VERSION 5.7 ;
  NOWIREEXTENSIONATPIN ON ;
  DIVIDERCHAR "/" ;
  BUSBITCHARS "[]" ;
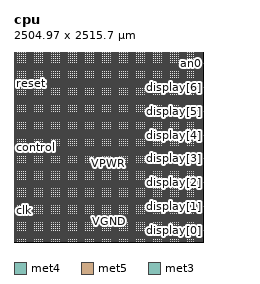
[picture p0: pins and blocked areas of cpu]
MACRO cpu
  CLASS BLOCK ;
  FOREIGN cpu ;
  ORIGIN 0.000 0.000 ;
  SIZE 2504.975 BY 2515.695 ;
  PIN VGND
    DIRECTION INOUT ;
    USE GROUND ;
    PORT
      LAYER met4 ;
        RECT 13.020 10.640 14.620 2502.640 ;
    END
    PORT
      LAYER met4 ;
        RECT 38.020 10.640 39.620 2502.640 ;
    END
    PORT
      LAYER met4 ;
        RECT 63.020 10.640 64.620 2502.640 ;
    END
    PORT
      LAYER met4 ;
        RECT 88.020 10.640 89.620 2502.640 ;
    END
    PORT
      LAYER met4 ;
        RECT 113.020 10.640 114.620 2502.640 ;
    END
    PORT
      LAYER met4 ;
        RECT 138.020 10.640 139.620 2502.640 ;
    END
    PORT
      LAYER met4 ;
        RECT 163.020 10.640 164.620 2502.640 ;
    END
    PORT
      LAYER met4 ;
        RECT 188.020 10.640 189.620 2502.640 ;
    END
    PORT
      LAYER met4 ;
        RECT 213.020 10.640 214.620 2502.640 ;
    END
    PORT
      LAYER met4 ;
        RECT 238.020 10.640 239.620 2502.640 ;
    END
    PORT
      LAYER met4 ;
        RECT 263.020 10.640 264.620 2502.640 ;
    END
    PORT
      LAYER met4 ;
        RECT 288.020 10.640 289.620 2502.640 ;
    END
    PORT
      LAYER met4 ;
        RECT 313.020 10.640 314.620 2502.640 ;
    END
    PORT
      LAYER met4 ;
        RECT 338.020 10.640 339.620 2502.640 ;
    END
    PORT
      LAYER met4 ;
        RECT 363.020 10.640 364.620 2502.640 ;
    END
    PORT
      LAYER met4 ;
        RECT 388.020 10.640 389.620 2502.640 ;
    END
    PORT
      LAYER met4 ;
        RECT 413.020 10.640 414.620 2502.640 ;
    END
    PORT
      LAYER met4 ;
        RECT 438.020 10.640 439.620 2502.640 ;
    END
    PORT
      LAYER met4 ;
        RECT 463.020 10.640 464.620 2502.640 ;
    END
    PORT
      LAYER met4 ;
        RECT 488.020 10.640 489.620 2502.640 ;
    END
    PORT
      LAYER met4 ;
        RECT 513.020 10.640 514.620 2502.640 ;
    END
    PORT
      LAYER met4 ;
        RECT 538.020 10.640 539.620 2502.640 ;
    END
    PORT
      LAYER met4 ;
        RECT 563.020 10.640 564.620 2502.640 ;
    END
    PORT
      LAYER met4 ;
        RECT 588.020 10.640 589.620 2502.640 ;
    END
    PORT
      LAYER met4 ;
        RECT 613.020 10.640 614.620 2502.640 ;
    END
    PORT
      LAYER met4 ;
        RECT 638.020 10.640 639.620 2502.640 ;
    END
    PORT
      LAYER met4 ;
        RECT 663.020 10.640 664.620 2502.640 ;
    END
    PORT
      LAYER met4 ;
        RECT 688.020 10.640 689.620 2502.640 ;
    END
    PORT
      LAYER met4 ;
        RECT 713.020 10.640 714.620 2502.640 ;
    END
    PORT
      LAYER met4 ;
        RECT 738.020 10.640 739.620 2502.640 ;
    END
    PORT
      LAYER met4 ;
        RECT 763.020 10.640 764.620 2502.640 ;
    END
    PORT
      LAYER met4 ;
        RECT 788.020 10.640 789.620 2502.640 ;
    END
    PORT
      LAYER met4 ;
        RECT 813.020 10.640 814.620 2502.640 ;
    END
    PORT
      LAYER met4 ;
        RECT 838.020 10.640 839.620 2502.640 ;
    END
    PORT
      LAYER met4 ;
        RECT 863.020 10.640 864.620 2502.640 ;
    END
    PORT
      LAYER met4 ;
        RECT 888.020 10.640 889.620 2502.640 ;
    END
    PORT
      LAYER met4 ;
        RECT 913.020 10.640 914.620 2502.640 ;
    END
    PORT
      LAYER met4 ;
        RECT 938.020 10.640 939.620 2502.640 ;
    END
    PORT
      LAYER met4 ;
        RECT 963.020 10.640 964.620 2502.640 ;
    END
    PORT
      LAYER met4 ;
        RECT 988.020 10.640 989.620 2502.640 ;
    END
    PORT
      LAYER met4 ;
        RECT 1013.020 10.640 1014.620 2502.640 ;
    END
    PORT
      LAYER met4 ;
        RECT 1038.020 10.640 1039.620 2502.640 ;
    END
    PORT
      LAYER met4 ;
        RECT 1063.020 10.640 1064.620 2502.640 ;
    END
    PORT
      LAYER met4 ;
        RECT 1088.020 10.640 1089.620 2502.640 ;
    END
    PORT
      LAYER met4 ;
        RECT 1113.020 10.640 1114.620 2502.640 ;
    END
    PORT
      LAYER met4 ;
        RECT 1138.020 10.640 1139.620 2502.640 ;
    END
    PORT
      LAYER met4 ;
        RECT 1163.020 10.640 1164.620 2502.640 ;
    END
    PORT
      LAYER met4 ;
        RECT 1188.020 10.640 1189.620 2502.640 ;
    END
    PORT
      LAYER met4 ;
        RECT 1213.020 10.640 1214.620 2502.640 ;
    END
    PORT
      LAYER met4 ;
        RECT 1238.020 10.640 1239.620 2502.640 ;
    END
    PORT
      LAYER met4 ;
        RECT 1263.020 10.640 1264.620 2502.640 ;
    END
    PORT
      LAYER met4 ;
        RECT 1288.020 10.640 1289.620 2502.640 ;
    END
    PORT
      LAYER met4 ;
        RECT 1313.020 10.640 1314.620 2502.640 ;
    END
    PORT
      LAYER met4 ;
        RECT 1338.020 10.640 1339.620 2502.640 ;
    END
    PORT
      LAYER met4 ;
        RECT 1363.020 10.640 1364.620 2502.640 ;
    END
    PORT
      LAYER met4 ;
        RECT 1388.020 10.640 1389.620 2502.640 ;
    END
    PORT
      LAYER met4 ;
        RECT 1413.020 10.640 1414.620 2502.640 ;
    END
    PORT
      LAYER met4 ;
        RECT 1438.020 10.640 1439.620 2502.640 ;
    END
    PORT
      LAYER met4 ;
        RECT 1463.020 10.640 1464.620 2502.640 ;
    END
    PORT
      LAYER met4 ;
        RECT 1488.020 10.640 1489.620 2502.640 ;
    END
    PORT
      LAYER met4 ;
        RECT 1513.020 10.640 1514.620 2502.640 ;
    END
    PORT
      LAYER met4 ;
        RECT 1538.020 10.640 1539.620 2502.640 ;
    END
    PORT
      LAYER met4 ;
        RECT 1563.020 10.640 1564.620 2502.640 ;
    END
    PORT
      LAYER met4 ;
        RECT 1588.020 10.640 1589.620 2502.640 ;
    END
    PORT
      LAYER met4 ;
        RECT 1613.020 10.640 1614.620 2502.640 ;
    END
    PORT
      LAYER met4 ;
        RECT 1638.020 10.640 1639.620 2502.640 ;
    END
    PORT
      LAYER met4 ;
        RECT 1663.020 10.640 1664.620 2502.640 ;
    END
    PORT
      LAYER met4 ;
        RECT 1688.020 10.640 1689.620 2502.640 ;
    END
    PORT
      LAYER met4 ;
        RECT 1713.020 10.640 1714.620 2502.640 ;
    END
    PORT
      LAYER met4 ;
        RECT 1738.020 10.640 1739.620 2502.640 ;
    END
    PORT
      LAYER met4 ;
        RECT 1763.020 10.640 1764.620 2502.640 ;
    END
    PORT
      LAYER met4 ;
        RECT 1788.020 10.640 1789.620 2502.640 ;
    END
    PORT
      LAYER met4 ;
        RECT 1813.020 10.640 1814.620 2502.640 ;
    END
    PORT
      LAYER met4 ;
        RECT 1838.020 10.640 1839.620 2502.640 ;
    END
    PORT
      LAYER met4 ;
        RECT 1863.020 10.640 1864.620 2502.640 ;
    END
    PORT
      LAYER met4 ;
        RECT 1888.020 10.640 1889.620 2502.640 ;
    END
    PORT
      LAYER met4 ;
        RECT 1913.020 10.640 1914.620 2502.640 ;
    END
    PORT
      LAYER met4 ;
        RECT 1938.020 10.640 1939.620 2502.640 ;
    END
    PORT
      LAYER met4 ;
        RECT 1963.020 10.640 1964.620 2502.640 ;
    END
    PORT
      LAYER met4 ;
        RECT 1988.020 10.640 1989.620 2502.640 ;
    END
    PORT
      LAYER met4 ;
        RECT 2013.020 10.640 2014.620 2502.640 ;
    END
    PORT
      LAYER met4 ;
        RECT 2038.020 10.640 2039.620 2502.640 ;
    END
    PORT
      LAYER met4 ;
        RECT 2063.020 10.640 2064.620 2502.640 ;
    END
    PORT
      LAYER met4 ;
        RECT 2088.020 10.640 2089.620 2502.640 ;
    END
    PORT
      LAYER met4 ;
        RECT 2113.020 10.640 2114.620 2502.640 ;
    END
    PORT
      LAYER met4 ;
        RECT 2138.020 10.640 2139.620 2502.640 ;
    END
    PORT
      LAYER met4 ;
        RECT 2163.020 10.640 2164.620 2502.640 ;
    END
    PORT
      LAYER met4 ;
        RECT 2188.020 10.640 2189.620 2502.640 ;
    END
    PORT
      LAYER met4 ;
        RECT 2213.020 10.640 2214.620 2502.640 ;
    END
    PORT
      LAYER met4 ;
        RECT 2238.020 10.640 2239.620 2502.640 ;
    END
    PORT
      LAYER met4 ;
        RECT 2263.020 10.640 2264.620 2502.640 ;
    END
    PORT
      LAYER met4 ;
        RECT 2288.020 10.640 2289.620 2502.640 ;
    END
    PORT
      LAYER met4 ;
        RECT 2313.020 10.640 2314.620 2502.640 ;
    END
    PORT
      LAYER met4 ;
        RECT 2338.020 10.640 2339.620 2502.640 ;
    END
    PORT
      LAYER met4 ;
        RECT 2363.020 10.640 2364.620 2502.640 ;
    END
    PORT
      LAYER met4 ;
        RECT 2388.020 10.640 2389.620 2502.640 ;
    END
    PORT
      LAYER met4 ;
        RECT 2413.020 10.640 2414.620 2502.640 ;
    END
    PORT
      LAYER met4 ;
        RECT 2438.020 10.640 2439.620 2502.640 ;
    END
    PORT
      LAYER met4 ;
        RECT 2463.020 10.640 2464.620 2502.640 ;
    END
    PORT
      LAYER met4 ;
        RECT 2488.020 10.640 2489.620 2502.640 ;
    END
    PORT
      LAYER met5 ;
        RECT 5.280 18.380 2499.420 19.980 ;
    END
    PORT
      LAYER met5 ;
        RECT 5.280 43.380 2499.420 44.980 ;
    END
    PORT
      LAYER met5 ;
        RECT 5.280 68.380 2499.420 69.980 ;
    END
    PORT
      LAYER met5 ;
        RECT 5.280 93.380 2499.420 94.980 ;
    END
    PORT
      LAYER met5 ;
        RECT 5.280 118.380 2499.420 119.980 ;
    END
    PORT
      LAYER met5 ;
        RECT 5.280 143.380 2499.420 144.980 ;
    END
    PORT
      LAYER met5 ;
        RECT 5.280 168.380 2499.420 169.980 ;
    END
    PORT
      LAYER met5 ;
        RECT 5.280 193.380 2499.420 194.980 ;
    END
    PORT
      LAYER met5 ;
        RECT 5.280 218.380 2499.420 219.980 ;
    END
    PORT
      LAYER met5 ;
        RECT 5.280 243.380 2499.420 244.980 ;
    END
    PORT
      LAYER met5 ;
        RECT 5.280 268.380 2499.420 269.980 ;
    END
    PORT
      LAYER met5 ;
        RECT 5.280 293.380 2499.420 294.980 ;
    END
    PORT
      LAYER met5 ;
        RECT 5.280 318.380 2499.420 319.980 ;
    END
    PORT
      LAYER met5 ;
        RECT 5.280 343.380 2499.420 344.980 ;
    END
    PORT
      LAYER met5 ;
        RECT 5.280 368.380 2499.420 369.980 ;
    END
    PORT
      LAYER met5 ;
        RECT 5.280 393.380 2499.420 394.980 ;
    END
    PORT
      LAYER met5 ;
        RECT 5.280 418.380 2499.420 419.980 ;
    END
    PORT
      LAYER met5 ;
        RECT 5.280 443.380 2499.420 444.980 ;
    END
    PORT
      LAYER met5 ;
        RECT 5.280 468.380 2499.420 469.980 ;
    END
    PORT
      LAYER met5 ;
        RECT 5.280 493.380 2499.420 494.980 ;
    END
    PORT
      LAYER met5 ;
        RECT 5.280 518.380 2499.420 519.980 ;
    END
    PORT
      LAYER met5 ;
        RECT 5.280 543.380 2499.420 544.980 ;
    END
    PORT
      LAYER met5 ;
        RECT 5.280 568.380 2499.420 569.980 ;
    END
    PORT
      LAYER met5 ;
        RECT 5.280 593.380 2499.420 594.980 ;
    END
    PORT
      LAYER met5 ;
        RECT 5.280 618.380 2499.420 619.980 ;
    END
    PORT
      LAYER met5 ;
        RECT 5.280 643.380 2499.420 644.980 ;
    END
    PORT
      LAYER met5 ;
        RECT 5.280 668.380 2499.420 669.980 ;
    END
    PORT
      LAYER met5 ;
        RECT 5.280 693.380 2499.420 694.980 ;
    END
    PORT
      LAYER met5 ;
        RECT 5.280 718.380 2499.420 719.980 ;
    END
    PORT
      LAYER met5 ;
        RECT 5.280 743.380 2499.420 744.980 ;
    END
    PORT
      LAYER met5 ;
        RECT 5.280 768.380 2499.420 769.980 ;
    END
    PORT
      LAYER met5 ;
        RECT 5.280 793.380 2499.420 794.980 ;
    END
    PORT
      LAYER met5 ;
        RECT 5.280 818.380 2499.420 819.980 ;
    END
    PORT
      LAYER met5 ;
        RECT 5.280 843.380 2499.420 844.980 ;
    END
    PORT
      LAYER met5 ;
        RECT 5.280 868.380 2499.420 869.980 ;
    END
    PORT
      LAYER met5 ;
        RECT 5.280 893.380 2499.420 894.980 ;
    END
    PORT
      LAYER met5 ;
        RECT 5.280 918.380 2499.420 919.980 ;
    END
    PORT
      LAYER met5 ;
        RECT 5.280 943.380 2499.420 944.980 ;
    END
    PORT
      LAYER met5 ;
        RECT 5.280 968.380 2499.420 969.980 ;
    END
    PORT
      LAYER met5 ;
        RECT 5.280 993.380 2499.420 994.980 ;
    END
    PORT
      LAYER met5 ;
        RECT 5.280 1018.380 2499.420 1019.980 ;
    END
    PORT
      LAYER met5 ;
        RECT 5.280 1043.380 2499.420 1044.980 ;
    END
    PORT
      LAYER met5 ;
        RECT 5.280 1068.380 2499.420 1069.980 ;
    END
    PORT
      LAYER met5 ;
        RECT 5.280 1093.380 2499.420 1094.980 ;
    END
    PORT
      LAYER met5 ;
        RECT 5.280 1118.380 2499.420 1119.980 ;
    END
    PORT
      LAYER met5 ;
        RECT 5.280 1143.380 2499.420 1144.980 ;
    END
    PORT
      LAYER met5 ;
        RECT 5.280 1168.380 2499.420 1169.980 ;
    END
    PORT
      LAYER met5 ;
        RECT 5.280 1193.380 2499.420 1194.980 ;
    END
    PORT
      LAYER met5 ;
        RECT 5.280 1218.380 2499.420 1219.980 ;
    END
    PORT
      LAYER met5 ;
        RECT 5.280 1243.380 2499.420 1244.980 ;
    END
    PORT
      LAYER met5 ;
        RECT 5.280 1268.380 2499.420 1269.980 ;
    END
    PORT
      LAYER met5 ;
        RECT 5.280 1293.380 2499.420 1294.980 ;
    END
    PORT
      LAYER met5 ;
        RECT 5.280 1318.380 2499.420 1319.980 ;
    END
    PORT
      LAYER met5 ;
        RECT 5.280 1343.380 2499.420 1344.980 ;
    END
    PORT
      LAYER met5 ;
        RECT 5.280 1368.380 2499.420 1369.980 ;
    END
    PORT
      LAYER met5 ;
        RECT 5.280 1393.380 2499.420 1394.980 ;
    END
    PORT
      LAYER met5 ;
        RECT 5.280 1418.380 2499.420 1419.980 ;
    END
    PORT
      LAYER met5 ;
        RECT 5.280 1443.380 2499.420 1444.980 ;
    END
    PORT
      LAYER met5 ;
        RECT 5.280 1468.380 2499.420 1469.980 ;
    END
    PORT
      LAYER met5 ;
        RECT 5.280 1493.380 2499.420 1494.980 ;
    END
    PORT
      LAYER met5 ;
        RECT 5.280 1518.380 2499.420 1519.980 ;
    END
    PORT
      LAYER met5 ;
        RECT 5.280 1543.380 2499.420 1544.980 ;
    END
    PORT
      LAYER met5 ;
        RECT 5.280 1568.380 2499.420 1569.980 ;
    END
    PORT
      LAYER met5 ;
        RECT 5.280 1593.380 2499.420 1594.980 ;
    END
    PORT
      LAYER met5 ;
        RECT 5.280 1618.380 2499.420 1619.980 ;
    END
    PORT
      LAYER met5 ;
        RECT 5.280 1643.380 2499.420 1644.980 ;
    END
    PORT
      LAYER met5 ;
        RECT 5.280 1668.380 2499.420 1669.980 ;
    END
    PORT
      LAYER met5 ;
        RECT 5.280 1693.380 2499.420 1694.980 ;
    END
    PORT
      LAYER met5 ;
        RECT 5.280 1718.380 2499.420 1719.980 ;
    END
    PORT
      LAYER met5 ;
        RECT 5.280 1743.380 2499.420 1744.980 ;
    END
    PORT
      LAYER met5 ;
        RECT 5.280 1768.380 2499.420 1769.980 ;
    END
    PORT
      LAYER met5 ;
        RECT 5.280 1793.380 2499.420 1794.980 ;
    END
    PORT
      LAYER met5 ;
        RECT 5.280 1818.380 2499.420 1819.980 ;
    END
    PORT
      LAYER met5 ;
        RECT 5.280 1843.380 2499.420 1844.980 ;
    END
    PORT
      LAYER met5 ;
        RECT 5.280 1868.380 2499.420 1869.980 ;
    END
    PORT
      LAYER met5 ;
        RECT 5.280 1893.380 2499.420 1894.980 ;
    END
    PORT
      LAYER met5 ;
        RECT 5.280 1918.380 2499.420 1919.980 ;
    END
    PORT
      LAYER met5 ;
        RECT 5.280 1943.380 2499.420 1944.980 ;
    END
    PORT
      LAYER met5 ;
        RECT 5.280 1968.380 2499.420 1969.980 ;
    END
    PORT
      LAYER met5 ;
        RECT 5.280 1993.380 2499.420 1994.980 ;
    END
    PORT
      LAYER met5 ;
        RECT 5.280 2018.380 2499.420 2019.980 ;
    END
    PORT
      LAYER met5 ;
        RECT 5.280 2043.380 2499.420 2044.980 ;
    END
    PORT
      LAYER met5 ;
        RECT 5.280 2068.380 2499.420 2069.980 ;
    END
    PORT
      LAYER met5 ;
        RECT 5.280 2093.380 2499.420 2094.980 ;
    END
    PORT
      LAYER met5 ;
        RECT 5.280 2118.380 2499.420 2119.980 ;
    END
    PORT
      LAYER met5 ;
        RECT 5.280 2143.380 2499.420 2144.980 ;
    END
    PORT
      LAYER met5 ;
        RECT 5.280 2168.380 2499.420 2169.980 ;
    END
    PORT
      LAYER met5 ;
        RECT 5.280 2193.380 2499.420 2194.980 ;
    END
    PORT
      LAYER met5 ;
        RECT 5.280 2218.380 2499.420 2219.980 ;
    END
    PORT
      LAYER met5 ;
        RECT 5.280 2243.380 2499.420 2244.980 ;
    END
    PORT
      LAYER met5 ;
        RECT 5.280 2268.380 2499.420 2269.980 ;
    END
    PORT
      LAYER met5 ;
        RECT 5.280 2293.380 2499.420 2294.980 ;
    END
    PORT
      LAYER met5 ;
        RECT 5.280 2318.380 2499.420 2319.980 ;
    END
    PORT
      LAYER met5 ;
        RECT 5.280 2343.380 2499.420 2344.980 ;
    END
    PORT
      LAYER met5 ;
        RECT 5.280 2368.380 2499.420 2369.980 ;
    END
    PORT
      LAYER met5 ;
        RECT 5.280 2393.380 2499.420 2394.980 ;
    END
    PORT
      LAYER met5 ;
        RECT 5.280 2418.380 2499.420 2419.980 ;
    END
    PORT
      LAYER met5 ;
        RECT 5.280 2443.380 2499.420 2444.980 ;
    END
    PORT
      LAYER met5 ;
        RECT 5.280 2468.380 2499.420 2469.980 ;
    END
    PORT
      LAYER met5 ;
        RECT 5.280 2493.380 2499.420 2494.980 ;
    END
  END VGND
  PIN VPWR
    DIRECTION INOUT ;
    USE POWER ;
    PORT
      LAYER met4 ;
        RECT 9.720 10.640 11.320 2502.640 ;
    END
    PORT
      LAYER met4 ;
        RECT 34.720 10.640 36.320 2502.640 ;
    END
    PORT
      LAYER met4 ;
        RECT 59.720 10.640 61.320 2502.640 ;
    END
    PORT
      LAYER met4 ;
        RECT 84.720 10.640 86.320 2502.640 ;
    END
    PORT
      LAYER met4 ;
        RECT 109.720 10.640 111.320 2502.640 ;
    END
    PORT
      LAYER met4 ;
        RECT 134.720 10.640 136.320 2502.640 ;
    END
    PORT
      LAYER met4 ;
        RECT 159.720 10.640 161.320 2502.640 ;
    END
    PORT
      LAYER met4 ;
        RECT 184.720 10.640 186.320 2502.640 ;
    END
    PORT
      LAYER met4 ;
        RECT 209.720 10.640 211.320 2502.640 ;
    END
    PORT
      LAYER met4 ;
        RECT 234.720 10.640 236.320 2502.640 ;
    END
    PORT
      LAYER met4 ;
        RECT 259.720 10.640 261.320 2502.640 ;
    END
    PORT
      LAYER met4 ;
        RECT 284.720 10.640 286.320 2502.640 ;
    END
    PORT
      LAYER met4 ;
        RECT 309.720 10.640 311.320 2502.640 ;
    END
    PORT
      LAYER met4 ;
        RECT 334.720 10.640 336.320 2502.640 ;
    END
    PORT
      LAYER met4 ;
        RECT 359.720 10.640 361.320 2502.640 ;
    END
    PORT
      LAYER met4 ;
        RECT 384.720 10.640 386.320 2502.640 ;
    END
    PORT
      LAYER met4 ;
        RECT 409.720 10.640 411.320 2502.640 ;
    END
    PORT
      LAYER met4 ;
        RECT 434.720 10.640 436.320 2502.640 ;
    END
    PORT
      LAYER met4 ;
        RECT 459.720 10.640 461.320 2502.640 ;
    END
    PORT
      LAYER met4 ;
        RECT 484.720 10.640 486.320 2502.640 ;
    END
    PORT
      LAYER met4 ;
        RECT 509.720 10.640 511.320 2502.640 ;
    END
    PORT
      LAYER met4 ;
        RECT 534.720 10.640 536.320 2502.640 ;
    END
    PORT
      LAYER met4 ;
        RECT 559.720 10.640 561.320 2502.640 ;
    END
    PORT
      LAYER met4 ;
        RECT 584.720 10.640 586.320 2502.640 ;
    END
    PORT
      LAYER met4 ;
        RECT 609.720 10.640 611.320 2502.640 ;
    END
    PORT
      LAYER met4 ;
        RECT 634.720 10.640 636.320 2502.640 ;
    END
    PORT
      LAYER met4 ;
        RECT 659.720 10.640 661.320 2502.640 ;
    END
    PORT
      LAYER met4 ;
        RECT 684.720 10.640 686.320 2502.640 ;
    END
    PORT
      LAYER met4 ;
        RECT 709.720 10.640 711.320 2502.640 ;
    END
    PORT
      LAYER met4 ;
        RECT 734.720 10.640 736.320 2502.640 ;
    END
    PORT
      LAYER met4 ;
        RECT 759.720 10.640 761.320 2502.640 ;
    END
    PORT
      LAYER met4 ;
        RECT 784.720 10.640 786.320 2502.640 ;
    END
    PORT
      LAYER met4 ;
        RECT 809.720 10.640 811.320 2502.640 ;
    END
    PORT
      LAYER met4 ;
        RECT 834.720 10.640 836.320 2502.640 ;
    END
    PORT
      LAYER met4 ;
        RECT 859.720 10.640 861.320 2502.640 ;
    END
    PORT
      LAYER met4 ;
        RECT 884.720 10.640 886.320 2502.640 ;
    END
    PORT
      LAYER met4 ;
        RECT 909.720 10.640 911.320 2502.640 ;
    END
    PORT
      LAYER met4 ;
        RECT 934.720 10.640 936.320 2502.640 ;
    END
    PORT
      LAYER met4 ;
        RECT 959.720 10.640 961.320 2502.640 ;
    END
    PORT
      LAYER met4 ;
        RECT 984.720 10.640 986.320 2502.640 ;
    END
    PORT
      LAYER met4 ;
        RECT 1009.720 10.640 1011.320 2502.640 ;
    END
    PORT
      LAYER met4 ;
        RECT 1034.720 10.640 1036.320 2502.640 ;
    END
    PORT
      LAYER met4 ;
        RECT 1059.720 10.640 1061.320 2502.640 ;
    END
    PORT
      LAYER met4 ;
        RECT 1084.720 10.640 1086.320 2502.640 ;
    END
    PORT
      LAYER met4 ;
        RECT 1109.720 10.640 1111.320 2502.640 ;
    END
    PORT
      LAYER met4 ;
        RECT 1134.720 10.640 1136.320 2502.640 ;
    END
    PORT
      LAYER met4 ;
        RECT 1159.720 10.640 1161.320 2502.640 ;
    END
    PORT
      LAYER met4 ;
        RECT 1184.720 10.640 1186.320 2502.640 ;
    END
    PORT
      LAYER met4 ;
        RECT 1209.720 10.640 1211.320 2502.640 ;
    END
    PORT
      LAYER met4 ;
        RECT 1234.720 10.640 1236.320 2502.640 ;
    END
    PORT
      LAYER met4 ;
        RECT 1259.720 10.640 1261.320 2502.640 ;
    END
    PORT
      LAYER met4 ;
        RECT 1284.720 10.640 1286.320 2502.640 ;
    END
    PORT
      LAYER met4 ;
        RECT 1309.720 10.640 1311.320 2502.640 ;
    END
    PORT
      LAYER met4 ;
        RECT 1334.720 10.640 1336.320 2502.640 ;
    END
    PORT
      LAYER met4 ;
        RECT 1359.720 10.640 1361.320 2502.640 ;
    END
    PORT
      LAYER met4 ;
        RECT 1384.720 10.640 1386.320 2502.640 ;
    END
    PORT
      LAYER met4 ;
        RECT 1409.720 10.640 1411.320 2502.640 ;
    END
    PORT
      LAYER met4 ;
        RECT 1434.720 10.640 1436.320 2502.640 ;
    END
    PORT
      LAYER met4 ;
        RECT 1459.720 10.640 1461.320 2502.640 ;
    END
    PORT
      LAYER met4 ;
        RECT 1484.720 10.640 1486.320 2502.640 ;
    END
    PORT
      LAYER met4 ;
        RECT 1509.720 10.640 1511.320 2502.640 ;
    END
    PORT
      LAYER met4 ;
        RECT 1534.720 10.640 1536.320 2502.640 ;
    END
    PORT
      LAYER met4 ;
        RECT 1559.720 10.640 1561.320 2502.640 ;
    END
    PORT
      LAYER met4 ;
        RECT 1584.720 10.640 1586.320 2502.640 ;
    END
    PORT
      LAYER met4 ;
        RECT 1609.720 10.640 1611.320 2502.640 ;
    END
    PORT
      LAYER met4 ;
        RECT 1634.720 10.640 1636.320 2502.640 ;
    END
    PORT
      LAYER met4 ;
        RECT 1659.720 10.640 1661.320 2502.640 ;
    END
    PORT
      LAYER met4 ;
        RECT 1684.720 10.640 1686.320 2502.640 ;
    END
    PORT
      LAYER met4 ;
        RECT 1709.720 10.640 1711.320 2502.640 ;
    END
    PORT
      LAYER met4 ;
        RECT 1734.720 10.640 1736.320 2502.640 ;
    END
    PORT
      LAYER met4 ;
        RECT 1759.720 10.640 1761.320 2502.640 ;
    END
    PORT
      LAYER met4 ;
        RECT 1784.720 10.640 1786.320 2502.640 ;
    END
    PORT
      LAYER met4 ;
        RECT 1809.720 10.640 1811.320 2502.640 ;
    END
    PORT
      LAYER met4 ;
        RECT 1834.720 10.640 1836.320 2502.640 ;
    END
    PORT
      LAYER met4 ;
        RECT 1859.720 10.640 1861.320 2502.640 ;
    END
    PORT
      LAYER met4 ;
        RECT 1884.720 10.640 1886.320 2502.640 ;
    END
    PORT
      LAYER met4 ;
        RECT 1909.720 10.640 1911.320 2502.640 ;
    END
    PORT
      LAYER met4 ;
        RECT 1934.720 10.640 1936.320 2502.640 ;
    END
    PORT
      LAYER met4 ;
        RECT 1959.720 10.640 1961.320 2502.640 ;
    END
    PORT
      LAYER met4 ;
        RECT 1984.720 10.640 1986.320 2502.640 ;
    END
    PORT
      LAYER met4 ;
        RECT 2009.720 10.640 2011.320 2502.640 ;
    END
    PORT
      LAYER met4 ;
        RECT 2034.720 10.640 2036.320 2502.640 ;
    END
    PORT
      LAYER met4 ;
        RECT 2059.720 10.640 2061.320 2502.640 ;
    END
    PORT
      LAYER met4 ;
        RECT 2084.720 10.640 2086.320 2502.640 ;
    END
    PORT
      LAYER met4 ;
        RECT 2109.720 10.640 2111.320 2502.640 ;
    END
    PORT
      LAYER met4 ;
        RECT 2134.720 10.640 2136.320 2502.640 ;
    END
    PORT
      LAYER met4 ;
        RECT 2159.720 10.640 2161.320 2502.640 ;
    END
    PORT
      LAYER met4 ;
        RECT 2184.720 10.640 2186.320 2502.640 ;
    END
    PORT
      LAYER met4 ;
        RECT 2209.720 10.640 2211.320 2502.640 ;
    END
    PORT
      LAYER met4 ;
        RECT 2234.720 10.640 2236.320 2502.640 ;
    END
    PORT
      LAYER met4 ;
        RECT 2259.720 10.640 2261.320 2502.640 ;
    END
    PORT
      LAYER met4 ;
        RECT 2284.720 10.640 2286.320 2502.640 ;
    END
    PORT
      LAYER met4 ;
        RECT 2309.720 10.640 2311.320 2502.640 ;
    END
    PORT
      LAYER met4 ;
        RECT 2334.720 10.640 2336.320 2502.640 ;
    END
    PORT
      LAYER met4 ;
        RECT 2359.720 10.640 2361.320 2502.640 ;
    END
    PORT
      LAYER met4 ;
        RECT 2384.720 10.640 2386.320 2502.640 ;
    END
    PORT
      LAYER met4 ;
        RECT 2409.720 10.640 2411.320 2502.640 ;
    END
    PORT
      LAYER met4 ;
        RECT 2434.720 10.640 2436.320 2502.640 ;
    END
    PORT
      LAYER met4 ;
        RECT 2459.720 10.640 2461.320 2502.640 ;
    END
    PORT
      LAYER met4 ;
        RECT 2484.720 10.640 2486.320 2502.640 ;
    END
    PORT
      LAYER met5 ;
        RECT 5.280 15.080 2499.420 16.680 ;
    END
    PORT
      LAYER met5 ;
        RECT 5.280 40.080 2499.420 41.680 ;
    END
    PORT
      LAYER met5 ;
        RECT 5.280 65.080 2499.420 66.680 ;
    END
    PORT
      LAYER met5 ;
        RECT 5.280 90.080 2499.420 91.680 ;
    END
    PORT
      LAYER met5 ;
        RECT 5.280 115.080 2499.420 116.680 ;
    END
    PORT
      LAYER met5 ;
        RECT 5.280 140.080 2499.420 141.680 ;
    END
    PORT
      LAYER met5 ;
        RECT 5.280 165.080 2499.420 166.680 ;
    END
    PORT
      LAYER met5 ;
        RECT 5.280 190.080 2499.420 191.680 ;
    END
    PORT
      LAYER met5 ;
        RECT 5.280 215.080 2499.420 216.680 ;
    END
    PORT
      LAYER met5 ;
        RECT 5.280 240.080 2499.420 241.680 ;
    END
    PORT
      LAYER met5 ;
        RECT 5.280 265.080 2499.420 266.680 ;
    END
    PORT
      LAYER met5 ;
        RECT 5.280 290.080 2499.420 291.680 ;
    END
    PORT
      LAYER met5 ;
        RECT 5.280 315.080 2499.420 316.680 ;
    END
    PORT
      LAYER met5 ;
        RECT 5.280 340.080 2499.420 341.680 ;
    END
    PORT
      LAYER met5 ;
        RECT 5.280 365.080 2499.420 366.680 ;
    END
    PORT
      LAYER met5 ;
        RECT 5.280 390.080 2499.420 391.680 ;
    END
    PORT
      LAYER met5 ;
        RECT 5.280 415.080 2499.420 416.680 ;
    END
    PORT
      LAYER met5 ;
        RECT 5.280 440.080 2499.420 441.680 ;
    END
    PORT
      LAYER met5 ;
        RECT 5.280 465.080 2499.420 466.680 ;
    END
    PORT
      LAYER met5 ;
        RECT 5.280 490.080 2499.420 491.680 ;
    END
    PORT
      LAYER met5 ;
        RECT 5.280 515.080 2499.420 516.680 ;
    END
    PORT
      LAYER met5 ;
        RECT 5.280 540.080 2499.420 541.680 ;
    END
    PORT
      LAYER met5 ;
        RECT 5.280 565.080 2499.420 566.680 ;
    END
    PORT
      LAYER met5 ;
        RECT 5.280 590.080 2499.420 591.680 ;
    END
    PORT
      LAYER met5 ;
        RECT 5.280 615.080 2499.420 616.680 ;
    END
    PORT
      LAYER met5 ;
        RECT 5.280 640.080 2499.420 641.680 ;
    END
    PORT
      LAYER met5 ;
        RECT 5.280 665.080 2499.420 666.680 ;
    END
    PORT
      LAYER met5 ;
        RECT 5.280 690.080 2499.420 691.680 ;
    END
    PORT
      LAYER met5 ;
        RECT 5.280 715.080 2499.420 716.680 ;
    END
    PORT
      LAYER met5 ;
        RECT 5.280 740.080 2499.420 741.680 ;
    END
    PORT
      LAYER met5 ;
        RECT 5.280 765.080 2499.420 766.680 ;
    END
    PORT
      LAYER met5 ;
        RECT 5.280 790.080 2499.420 791.680 ;
    END
    PORT
      LAYER met5 ;
        RECT 5.280 815.080 2499.420 816.680 ;
    END
    PORT
      LAYER met5 ;
        RECT 5.280 840.080 2499.420 841.680 ;
    END
    PORT
      LAYER met5 ;
        RECT 5.280 865.080 2499.420 866.680 ;
    END
    PORT
      LAYER met5 ;
        RECT 5.280 890.080 2499.420 891.680 ;
    END
    PORT
      LAYER met5 ;
        RECT 5.280 915.080 2499.420 916.680 ;
    END
    PORT
      LAYER met5 ;
        RECT 5.280 940.080 2499.420 941.680 ;
    END
    PORT
      LAYER met5 ;
        RECT 5.280 965.080 2499.420 966.680 ;
    END
    PORT
      LAYER met5 ;
        RECT 5.280 990.080 2499.420 991.680 ;
    END
    PORT
      LAYER met5 ;
        RECT 5.280 1015.080 2499.420 1016.680 ;
    END
    PORT
      LAYER met5 ;
        RECT 5.280 1040.080 2499.420 1041.680 ;
    END
    PORT
      LAYER met5 ;
        RECT 5.280 1065.080 2499.420 1066.680 ;
    END
    PORT
      LAYER met5 ;
        RECT 5.280 1090.080 2499.420 1091.680 ;
    END
    PORT
      LAYER met5 ;
        RECT 5.280 1115.080 2499.420 1116.680 ;
    END
    PORT
      LAYER met5 ;
        RECT 5.280 1140.080 2499.420 1141.680 ;
    END
    PORT
      LAYER met5 ;
        RECT 5.280 1165.080 2499.420 1166.680 ;
    END
    PORT
      LAYER met5 ;
        RECT 5.280 1190.080 2499.420 1191.680 ;
    END
    PORT
      LAYER met5 ;
        RECT 5.280 1215.080 2499.420 1216.680 ;
    END
    PORT
      LAYER met5 ;
        RECT 5.280 1240.080 2499.420 1241.680 ;
    END
    PORT
      LAYER met5 ;
        RECT 5.280 1265.080 2499.420 1266.680 ;
    END
    PORT
      LAYER met5 ;
        RECT 5.280 1290.080 2499.420 1291.680 ;
    END
    PORT
      LAYER met5 ;
        RECT 5.280 1315.080 2499.420 1316.680 ;
    END
    PORT
      LAYER met5 ;
        RECT 5.280 1340.080 2499.420 1341.680 ;
    END
    PORT
      LAYER met5 ;
        RECT 5.280 1365.080 2499.420 1366.680 ;
    END
    PORT
      LAYER met5 ;
        RECT 5.280 1390.080 2499.420 1391.680 ;
    END
    PORT
      LAYER met5 ;
        RECT 5.280 1415.080 2499.420 1416.680 ;
    END
    PORT
      LAYER met5 ;
        RECT 5.280 1440.080 2499.420 1441.680 ;
    END
    PORT
      LAYER met5 ;
        RECT 5.280 1465.080 2499.420 1466.680 ;
    END
    PORT
      LAYER met5 ;
        RECT 5.280 1490.080 2499.420 1491.680 ;
    END
    PORT
      LAYER met5 ;
        RECT 5.280 1515.080 2499.420 1516.680 ;
    END
    PORT
      LAYER met5 ;
        RECT 5.280 1540.080 2499.420 1541.680 ;
    END
    PORT
      LAYER met5 ;
        RECT 5.280 1565.080 2499.420 1566.680 ;
    END
    PORT
      LAYER met5 ;
        RECT 5.280 1590.080 2499.420 1591.680 ;
    END
    PORT
      LAYER met5 ;
        RECT 5.280 1615.080 2499.420 1616.680 ;
    END
    PORT
      LAYER met5 ;
        RECT 5.280 1640.080 2499.420 1641.680 ;
    END
    PORT
      LAYER met5 ;
        RECT 5.280 1665.080 2499.420 1666.680 ;
    END
    PORT
      LAYER met5 ;
        RECT 5.280 1690.080 2499.420 1691.680 ;
    END
    PORT
      LAYER met5 ;
        RECT 5.280 1715.080 2499.420 1716.680 ;
    END
    PORT
      LAYER met5 ;
        RECT 5.280 1740.080 2499.420 1741.680 ;
    END
    PORT
      LAYER met5 ;
        RECT 5.280 1765.080 2499.420 1766.680 ;
    END
    PORT
      LAYER met5 ;
        RECT 5.280 1790.080 2499.420 1791.680 ;
    END
    PORT
      LAYER met5 ;
        RECT 5.280 1815.080 2499.420 1816.680 ;
    END
    PORT
      LAYER met5 ;
        RECT 5.280 1840.080 2499.420 1841.680 ;
    END
    PORT
      LAYER met5 ;
        RECT 5.280 1865.080 2499.420 1866.680 ;
    END
    PORT
      LAYER met5 ;
        RECT 5.280 1890.080 2499.420 1891.680 ;
    END
    PORT
      LAYER met5 ;
        RECT 5.280 1915.080 2499.420 1916.680 ;
    END
    PORT
      LAYER met5 ;
        RECT 5.280 1940.080 2499.420 1941.680 ;
    END
    PORT
      LAYER met5 ;
        RECT 5.280 1965.080 2499.420 1966.680 ;
    END
    PORT
      LAYER met5 ;
        RECT 5.280 1990.080 2499.420 1991.680 ;
    END
    PORT
      LAYER met5 ;
        RECT 5.280 2015.080 2499.420 2016.680 ;
    END
    PORT
      LAYER met5 ;
        RECT 5.280 2040.080 2499.420 2041.680 ;
    END
    PORT
      LAYER met5 ;
        RECT 5.280 2065.080 2499.420 2066.680 ;
    END
    PORT
      LAYER met5 ;
        RECT 5.280 2090.080 2499.420 2091.680 ;
    END
    PORT
      LAYER met5 ;
        RECT 5.280 2115.080 2499.420 2116.680 ;
    END
    PORT
      LAYER met5 ;
        RECT 5.280 2140.080 2499.420 2141.680 ;
    END
    PORT
      LAYER met5 ;
        RECT 5.280 2165.080 2499.420 2166.680 ;
    END
    PORT
      LAYER met5 ;
        RECT 5.280 2190.080 2499.420 2191.680 ;
    END
    PORT
      LAYER met5 ;
        RECT 5.280 2215.080 2499.420 2216.680 ;
    END
    PORT
      LAYER met5 ;
        RECT 5.280 2240.080 2499.420 2241.680 ;
    END
    PORT
      LAYER met5 ;
        RECT 5.280 2265.080 2499.420 2266.680 ;
    END
    PORT
      LAYER met5 ;
        RECT 5.280 2290.080 2499.420 2291.680 ;
    END
    PORT
      LAYER met5 ;
        RECT 5.280 2315.080 2499.420 2316.680 ;
    END
    PORT
      LAYER met5 ;
        RECT 5.280 2340.080 2499.420 2341.680 ;
    END
    PORT
      LAYER met5 ;
        RECT 5.280 2365.080 2499.420 2366.680 ;
    END
    PORT
      LAYER met5 ;
        RECT 5.280 2390.080 2499.420 2391.680 ;
    END
    PORT
      LAYER met5 ;
        RECT 5.280 2415.080 2499.420 2416.680 ;
    END
    PORT
      LAYER met5 ;
        RECT 5.280 2440.080 2499.420 2441.680 ;
    END
    PORT
      LAYER met5 ;
        RECT 5.280 2465.080 2499.420 2466.680 ;
    END
    PORT
      LAYER met5 ;
        RECT 5.280 2490.080 2499.420 2491.680 ;
    END
  END VPWR
  PIN an0
    DIRECTION OUTPUT ;
    USE SIGNAL ;
    PORT
      LAYER met3 ;
        RECT 2500.975 2356.920 2504.975 2357.520 ;
    END
  END an0
  PIN clk
    DIRECTION INPUT ;
    USE SIGNAL ;
    ANTENNAGATEAREA 0.852000 ;
    ANTENNADIFFAREA 0.869400 ;
    PORT
      LAYER met3 ;
        RECT 0.000 418.920 4.000 419.520 ;
    END
  END clk
  PIN control
    DIRECTION INPUT ;
    USE SIGNAL ;
    ANTENNAGATEAREA 0.990000 ;
    PORT
      LAYER met3 ;
        RECT 0.000 1256.680 4.000 1257.280 ;
    END
  END control
  PIN display[0]
    DIRECTION OUTPUT ;
    USE SIGNAL ;
    ANTENNADIFFAREA 0.340600 ;
    PORT
      LAYER met3 ;
        RECT 2500.975 157.800 2504.975 158.400 ;
    END
  END display[0]
  PIN display[1]
    DIRECTION OUTPUT ;
    USE SIGNAL ;
    ANTENNADIFFAREA 0.340600 ;
    PORT
      LAYER met3 ;
        RECT 2500.975 471.960 2504.975 472.560 ;
    END
  END display[1]
  PIN display[2]
    DIRECTION OUTPUT ;
    USE SIGNAL ;
    ANTENNADIFFAREA 0.340600 ;
    PORT
      LAYER met3 ;
        RECT 2500.975 786.120 2504.975 786.720 ;
    END
  END display[2]
  PIN display[3]
    DIRECTION OUTPUT ;
    USE SIGNAL ;
    ANTENNADIFFAREA 0.340600 ;
    PORT
      LAYER met3 ;
        RECT 2500.975 1100.280 2504.975 1100.880 ;
    END
  END display[3]
  PIN display[4]
    DIRECTION OUTPUT ;
    USE SIGNAL ;
    ANTENNADIFFAREA 0.340600 ;
    PORT
      LAYER met3 ;
        RECT 2500.975 1414.440 2504.975 1415.040 ;
    END
  END display[4]
  PIN display[5]
    DIRECTION OUTPUT ;
    USE SIGNAL ;
    ANTENNADIFFAREA 0.340600 ;
    PORT
      LAYER met3 ;
        RECT 2500.975 1728.600 2504.975 1729.200 ;
    END
  END display[5]
  PIN display[6]
    DIRECTION OUTPUT ;
    USE SIGNAL ;
    ANTENNADIFFAREA 0.340600 ;
    PORT
      LAYER met3 ;
        RECT 2500.975 2042.760 2504.975 2043.360 ;
    END
  END display[6]
  PIN reset
    DIRECTION INPUT ;
    USE SIGNAL ;
    ANTENNAGATEAREA 0.990000 ;
    PORT
      LAYER met3 ;
        RECT 0.000 2094.440 4.000 2095.040 ;
    END
  END reset
  OBS
      LAYER nwell ;
        RECT 5.330 10.795 2499.370 2502.485 ;
      LAYER li1 ;
        RECT 5.520 10.795 2499.180 2502.485 ;
      LAYER met1 ;
        RECT 2.830 9.220 2501.870 2502.640 ;
      LAYER met2 ;
        RECT 0.550 9.190 2501.840 2502.585 ;
      LAYER met3 ;
        RECT 0.525 2357.920 2501.415 2502.565 ;
        RECT 0.525 2356.520 2500.575 2357.920 ;
        RECT 0.525 2095.440 2501.415 2356.520 ;
        RECT 4.400 2094.040 2501.415 2095.440 ;
        RECT 0.525 2043.760 2501.415 2094.040 ;
        RECT 0.525 2042.360 2500.575 2043.760 ;
        RECT 0.525 1729.600 2501.415 2042.360 ;
        RECT 0.525 1728.200 2500.575 1729.600 ;
        RECT 0.525 1415.440 2501.415 1728.200 ;
        RECT 0.525 1414.040 2500.575 1415.440 ;
        RECT 0.525 1257.680 2501.415 1414.040 ;
        RECT 4.400 1256.280 2501.415 1257.680 ;
        RECT 0.525 1101.280 2501.415 1256.280 ;
        RECT 0.525 1099.880 2500.575 1101.280 ;
        RECT 0.525 787.120 2501.415 1099.880 ;
        RECT 0.525 785.720 2500.575 787.120 ;
        RECT 0.525 472.960 2501.415 785.720 ;
        RECT 0.525 471.560 2500.575 472.960 ;
        RECT 0.525 419.920 2501.415 471.560 ;
        RECT 4.400 418.520 2501.415 419.920 ;
        RECT 0.525 158.800 2501.415 418.520 ;
        RECT 0.525 157.400 2500.575 158.800 ;
        RECT 0.525 10.715 2501.415 157.400 ;
      LAYER met4 ;
        RECT 7.655 15.135 9.320 2496.105 ;
        RECT 11.720 15.135 12.620 2496.105 ;
        RECT 15.020 15.135 34.320 2496.105 ;
        RECT 36.720 15.135 37.620 2496.105 ;
        RECT 40.020 15.135 59.320 2496.105 ;
        RECT 61.720 15.135 62.620 2496.105 ;
        RECT 65.020 15.135 84.320 2496.105 ;
        RECT 86.720 15.135 87.620 2496.105 ;
        RECT 90.020 15.135 109.320 2496.105 ;
        RECT 111.720 15.135 112.620 2496.105 ;
        RECT 115.020 15.135 134.320 2496.105 ;
        RECT 136.720 15.135 137.620 2496.105 ;
        RECT 140.020 15.135 159.320 2496.105 ;
        RECT 161.720 15.135 162.620 2496.105 ;
        RECT 165.020 15.135 184.320 2496.105 ;
        RECT 186.720 15.135 187.620 2496.105 ;
        RECT 190.020 15.135 209.320 2496.105 ;
        RECT 211.720 15.135 212.620 2496.105 ;
        RECT 215.020 15.135 234.320 2496.105 ;
        RECT 236.720 15.135 237.620 2496.105 ;
        RECT 240.020 15.135 259.320 2496.105 ;
        RECT 261.720 15.135 262.620 2496.105 ;
        RECT 265.020 15.135 284.320 2496.105 ;
        RECT 286.720 15.135 287.620 2496.105 ;
        RECT 290.020 15.135 309.320 2496.105 ;
        RECT 311.720 15.135 312.620 2496.105 ;
        RECT 315.020 15.135 334.320 2496.105 ;
        RECT 336.720 15.135 337.620 2496.105 ;
        RECT 340.020 15.135 359.320 2496.105 ;
        RECT 361.720 15.135 362.620 2496.105 ;
        RECT 365.020 15.135 384.320 2496.105 ;
        RECT 386.720 15.135 387.620 2496.105 ;
        RECT 390.020 15.135 409.320 2496.105 ;
        RECT 411.720 15.135 412.620 2496.105 ;
        RECT 415.020 15.135 434.320 2496.105 ;
        RECT 436.720 15.135 437.620 2496.105 ;
        RECT 440.020 15.135 459.320 2496.105 ;
        RECT 461.720 15.135 462.620 2496.105 ;
        RECT 465.020 15.135 484.320 2496.105 ;
        RECT 486.720 15.135 487.620 2496.105 ;
        RECT 490.020 15.135 509.320 2496.105 ;
        RECT 511.720 15.135 512.620 2496.105 ;
        RECT 515.020 15.135 534.320 2496.105 ;
        RECT 536.720 15.135 537.620 2496.105 ;
        RECT 540.020 15.135 559.320 2496.105 ;
        RECT 561.720 15.135 562.620 2496.105 ;
        RECT 565.020 15.135 584.320 2496.105 ;
        RECT 586.720 15.135 587.620 2496.105 ;
        RECT 590.020 15.135 609.320 2496.105 ;
        RECT 611.720 15.135 612.620 2496.105 ;
        RECT 615.020 15.135 634.320 2496.105 ;
        RECT 636.720 15.135 637.620 2496.105 ;
        RECT 640.020 15.135 659.320 2496.105 ;
        RECT 661.720 15.135 662.620 2496.105 ;
        RECT 665.020 15.135 684.320 2496.105 ;
        RECT 686.720 15.135 687.620 2496.105 ;
        RECT 690.020 15.135 709.320 2496.105 ;
        RECT 711.720 15.135 712.620 2496.105 ;
        RECT 715.020 15.135 734.320 2496.105 ;
        RECT 736.720 15.135 737.620 2496.105 ;
        RECT 740.020 15.135 759.320 2496.105 ;
        RECT 761.720 15.135 762.620 2496.105 ;
        RECT 765.020 15.135 784.320 2496.105 ;
        RECT 786.720 15.135 787.620 2496.105 ;
        RECT 790.020 15.135 809.320 2496.105 ;
        RECT 811.720 15.135 812.620 2496.105 ;
        RECT 815.020 15.135 834.320 2496.105 ;
        RECT 836.720 15.135 837.620 2496.105 ;
        RECT 840.020 15.135 859.320 2496.105 ;
        RECT 861.720 15.135 862.620 2496.105 ;
        RECT 865.020 15.135 884.320 2496.105 ;
        RECT 886.720 15.135 887.620 2496.105 ;
        RECT 890.020 15.135 909.320 2496.105 ;
        RECT 911.720 15.135 912.620 2496.105 ;
        RECT 915.020 15.135 934.320 2496.105 ;
        RECT 936.720 15.135 937.620 2496.105 ;
        RECT 940.020 15.135 959.320 2496.105 ;
        RECT 961.720 15.135 962.620 2496.105 ;
        RECT 965.020 15.135 984.320 2496.105 ;
        RECT 986.720 15.135 987.620 2496.105 ;
        RECT 990.020 15.135 1009.320 2496.105 ;
        RECT 1011.720 15.135 1012.620 2496.105 ;
        RECT 1015.020 15.135 1034.320 2496.105 ;
        RECT 1036.720 15.135 1037.620 2496.105 ;
        RECT 1040.020 15.135 1059.320 2496.105 ;
        RECT 1061.720 15.135 1062.620 2496.105 ;
        RECT 1065.020 15.135 1084.320 2496.105 ;
        RECT 1086.720 15.135 1087.620 2496.105 ;
        RECT 1090.020 15.135 1109.320 2496.105 ;
        RECT 1111.720 15.135 1112.620 2496.105 ;
        RECT 1115.020 15.135 1134.320 2496.105 ;
        RECT 1136.720 15.135 1137.620 2496.105 ;
        RECT 1140.020 15.135 1159.320 2496.105 ;
        RECT 1161.720 15.135 1162.620 2496.105 ;
        RECT 1165.020 15.135 1184.320 2496.105 ;
        RECT 1186.720 15.135 1187.620 2496.105 ;
        RECT 1190.020 15.135 1209.320 2496.105 ;
        RECT 1211.720 15.135 1212.620 2496.105 ;
        RECT 1215.020 15.135 1234.320 2496.105 ;
        RECT 1236.720 15.135 1237.620 2496.105 ;
        RECT 1240.020 15.135 1259.320 2496.105 ;
        RECT 1261.720 15.135 1262.620 2496.105 ;
        RECT 1265.020 15.135 1284.320 2496.105 ;
        RECT 1286.720 15.135 1287.620 2496.105 ;
        RECT 1290.020 15.135 1309.320 2496.105 ;
        RECT 1311.720 15.135 1312.620 2496.105 ;
        RECT 1315.020 15.135 1334.320 2496.105 ;
        RECT 1336.720 15.135 1337.620 2496.105 ;
        RECT 1340.020 15.135 1359.320 2496.105 ;
        RECT 1361.720 15.135 1362.620 2496.105 ;
        RECT 1365.020 15.135 1384.320 2496.105 ;
        RECT 1386.720 15.135 1387.620 2496.105 ;
        RECT 1390.020 15.135 1409.320 2496.105 ;
        RECT 1411.720 15.135 1412.620 2496.105 ;
        RECT 1415.020 15.135 1434.320 2496.105 ;
        RECT 1436.720 15.135 1437.620 2496.105 ;
        RECT 1440.020 15.135 1459.320 2496.105 ;
        RECT 1461.720 15.135 1462.620 2496.105 ;
        RECT 1465.020 15.135 1484.320 2496.105 ;
        RECT 1486.720 15.135 1487.620 2496.105 ;
        RECT 1490.020 15.135 1509.320 2496.105 ;
        RECT 1511.720 15.135 1512.620 2496.105 ;
        RECT 1515.020 15.135 1534.320 2496.105 ;
        RECT 1536.720 15.135 1537.620 2496.105 ;
        RECT 1540.020 15.135 1559.320 2496.105 ;
        RECT 1561.720 15.135 1562.620 2496.105 ;
        RECT 1565.020 15.135 1584.320 2496.105 ;
        RECT 1586.720 15.135 1587.620 2496.105 ;
        RECT 1590.020 15.135 1609.320 2496.105 ;
        RECT 1611.720 15.135 1612.620 2496.105 ;
        RECT 1615.020 15.135 1634.320 2496.105 ;
        RECT 1636.720 15.135 1637.620 2496.105 ;
        RECT 1640.020 15.135 1659.320 2496.105 ;
        RECT 1661.720 15.135 1662.620 2496.105 ;
        RECT 1665.020 15.135 1684.320 2496.105 ;
        RECT 1686.720 15.135 1687.620 2496.105 ;
        RECT 1690.020 15.135 1709.320 2496.105 ;
        RECT 1711.720 15.135 1712.620 2496.105 ;
        RECT 1715.020 15.135 1734.320 2496.105 ;
        RECT 1736.720 15.135 1737.620 2496.105 ;
        RECT 1740.020 15.135 1759.320 2496.105 ;
        RECT 1761.720 15.135 1762.620 2496.105 ;
        RECT 1765.020 15.135 1784.320 2496.105 ;
        RECT 1786.720 15.135 1787.620 2496.105 ;
        RECT 1790.020 15.135 1809.320 2496.105 ;
        RECT 1811.720 15.135 1812.620 2496.105 ;
        RECT 1815.020 15.135 1834.320 2496.105 ;
        RECT 1836.720 15.135 1837.620 2496.105 ;
        RECT 1840.020 15.135 1859.320 2496.105 ;
        RECT 1861.720 15.135 1862.620 2496.105 ;
        RECT 1865.020 15.135 1884.320 2496.105 ;
        RECT 1886.720 15.135 1887.620 2496.105 ;
        RECT 1890.020 15.135 1909.320 2496.105 ;
        RECT 1911.720 15.135 1912.620 2496.105 ;
        RECT 1915.020 15.135 1934.320 2496.105 ;
        RECT 1936.720 15.135 1937.620 2496.105 ;
        RECT 1940.020 15.135 1959.320 2496.105 ;
        RECT 1961.720 15.135 1962.620 2496.105 ;
        RECT 1965.020 15.135 1984.320 2496.105 ;
        RECT 1986.720 15.135 1987.620 2496.105 ;
        RECT 1990.020 15.135 2009.320 2496.105 ;
        RECT 2011.720 15.135 2012.620 2496.105 ;
        RECT 2015.020 15.135 2034.320 2496.105 ;
        RECT 2036.720 15.135 2037.620 2496.105 ;
        RECT 2040.020 15.135 2059.320 2496.105 ;
        RECT 2061.720 15.135 2062.620 2496.105 ;
        RECT 2065.020 15.135 2084.320 2496.105 ;
        RECT 2086.720 15.135 2087.620 2496.105 ;
        RECT 2090.020 15.135 2109.320 2496.105 ;
        RECT 2111.720 15.135 2112.620 2496.105 ;
        RECT 2115.020 15.135 2134.320 2496.105 ;
        RECT 2136.720 15.135 2137.620 2496.105 ;
        RECT 2140.020 15.135 2159.320 2496.105 ;
        RECT 2161.720 15.135 2162.620 2496.105 ;
        RECT 2165.020 15.135 2184.320 2496.105 ;
        RECT 2186.720 15.135 2187.620 2496.105 ;
        RECT 2190.020 15.135 2209.320 2496.105 ;
        RECT 2211.720 15.135 2212.620 2496.105 ;
        RECT 2215.020 15.135 2234.320 2496.105 ;
        RECT 2236.720 15.135 2237.620 2496.105 ;
        RECT 2240.020 15.135 2259.320 2496.105 ;
        RECT 2261.720 15.135 2262.620 2496.105 ;
        RECT 2265.020 15.135 2284.320 2496.105 ;
        RECT 2286.720 15.135 2287.620 2496.105 ;
        RECT 2290.020 15.135 2309.320 2496.105 ;
        RECT 2311.720 15.135 2312.620 2496.105 ;
        RECT 2315.020 15.135 2334.320 2496.105 ;
        RECT 2336.720 15.135 2337.620 2496.105 ;
        RECT 2340.020 15.135 2359.320 2496.105 ;
        RECT 2361.720 15.135 2362.620 2496.105 ;
        RECT 2365.020 15.135 2384.320 2496.105 ;
        RECT 2386.720 15.135 2387.620 2496.105 ;
        RECT 2390.020 15.135 2409.320 2496.105 ;
        RECT 2411.720 15.135 2412.620 2496.105 ;
        RECT 2415.020 15.135 2434.320 2496.105 ;
        RECT 2436.720 15.135 2437.620 2496.105 ;
        RECT 2440.020 15.135 2459.320 2496.105 ;
        RECT 2461.720 15.135 2462.620 2496.105 ;
        RECT 2465.020 15.135 2484.320 2496.105 ;
        RECT 2486.720 15.135 2487.620 2496.105 ;
        RECT 2490.020 15.135 2497.930 2496.105 ;
      LAYER met5 ;
        RECT 193.780 1671.580 2498.140 1685.500 ;
        RECT 193.780 1646.580 2498.140 1663.480 ;
        RECT 193.780 1621.580 2498.140 1638.480 ;
        RECT 193.780 1596.580 2498.140 1613.480 ;
        RECT 193.780 1571.580 2498.140 1588.480 ;
        RECT 193.780 1546.580 2498.140 1563.480 ;
        RECT 193.780 1521.580 2498.140 1538.480 ;
        RECT 193.780 1496.580 2498.140 1513.480 ;
        RECT 193.780 1471.580 2498.140 1488.480 ;
        RECT 193.780 1446.580 2498.140 1463.480 ;
        RECT 193.780 1421.580 2498.140 1438.480 ;
        RECT 193.780 1396.580 2498.140 1413.480 ;
        RECT 193.780 1371.580 2498.140 1388.480 ;
        RECT 193.780 1346.580 2498.140 1363.480 ;
        RECT 193.780 1321.580 2498.140 1338.480 ;
        RECT 193.780 1296.580 2498.140 1313.480 ;
        RECT 193.780 1271.580 2498.140 1288.480 ;
        RECT 193.780 1246.580 2498.140 1263.480 ;
        RECT 193.780 1221.580 2498.140 1238.480 ;
        RECT 193.780 1196.580 2498.140 1213.480 ;
        RECT 193.780 1171.580 2498.140 1188.480 ;
        RECT 193.780 1146.580 2498.140 1163.480 ;
        RECT 193.780 1121.580 2498.140 1138.480 ;
        RECT 193.780 1096.580 2498.140 1113.480 ;
        RECT 193.780 1071.580 2498.140 1088.480 ;
        RECT 193.780 1046.580 2498.140 1063.480 ;
        RECT 193.780 1021.580 2498.140 1038.480 ;
        RECT 193.780 996.580 2498.140 1013.480 ;
        RECT 193.780 971.580 2498.140 988.480 ;
        RECT 193.780 946.580 2498.140 963.480 ;
        RECT 193.780 921.580 2498.140 938.480 ;
        RECT 193.780 896.580 2498.140 913.480 ;
        RECT 193.780 871.580 2498.140 888.480 ;
        RECT 193.780 846.580 2498.140 863.480 ;
        RECT 193.780 821.580 2498.140 838.480 ;
        RECT 193.780 796.580 2498.140 813.480 ;
        RECT 193.780 771.580 2498.140 788.480 ;
        RECT 193.780 746.580 2498.140 763.480 ;
        RECT 193.780 721.580 2498.140 738.480 ;
        RECT 193.780 696.580 2498.140 713.480 ;
        RECT 193.780 671.580 2498.140 688.480 ;
        RECT 193.780 646.580 2498.140 663.480 ;
        RECT 193.780 621.580 2498.140 638.480 ;
        RECT 193.780 596.580 2498.140 613.480 ;
        RECT 193.780 571.580 2498.140 588.480 ;
        RECT 193.780 546.580 2498.140 563.480 ;
        RECT 193.780 521.580 2498.140 538.480 ;
        RECT 193.780 496.580 2498.140 513.480 ;
        RECT 193.780 471.580 2498.140 488.480 ;
        RECT 193.780 446.580 2498.140 463.480 ;
        RECT 193.780 421.580 2498.140 438.480 ;
        RECT 193.780 396.580 2498.140 413.480 ;
        RECT 193.780 371.580 2498.140 388.480 ;
        RECT 193.780 346.580 2498.140 363.480 ;
        RECT 193.780 321.580 2498.140 338.480 ;
        RECT 193.780 296.580 2498.140 313.480 ;
        RECT 193.780 271.580 2498.140 288.480 ;
        RECT 193.780 246.580 2498.140 263.480 ;
        RECT 193.780 221.580 2498.140 238.480 ;
        RECT 193.780 196.580 2498.140 213.480 ;
        RECT 193.780 171.580 2498.140 188.480 ;
        RECT 193.780 160.700 2498.140 163.480 ;
  END
END cpu
END LIBRARY

